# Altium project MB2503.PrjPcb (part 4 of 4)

## Sheet USB_TypeC_DRP.SchDoc: USB Type-C DRP
size A3; DocumentNumber: 13; Revision: A-01; SheetNumber: 13; SheetTotal: 17; Project: STM32MP15-BATTERY BOARD

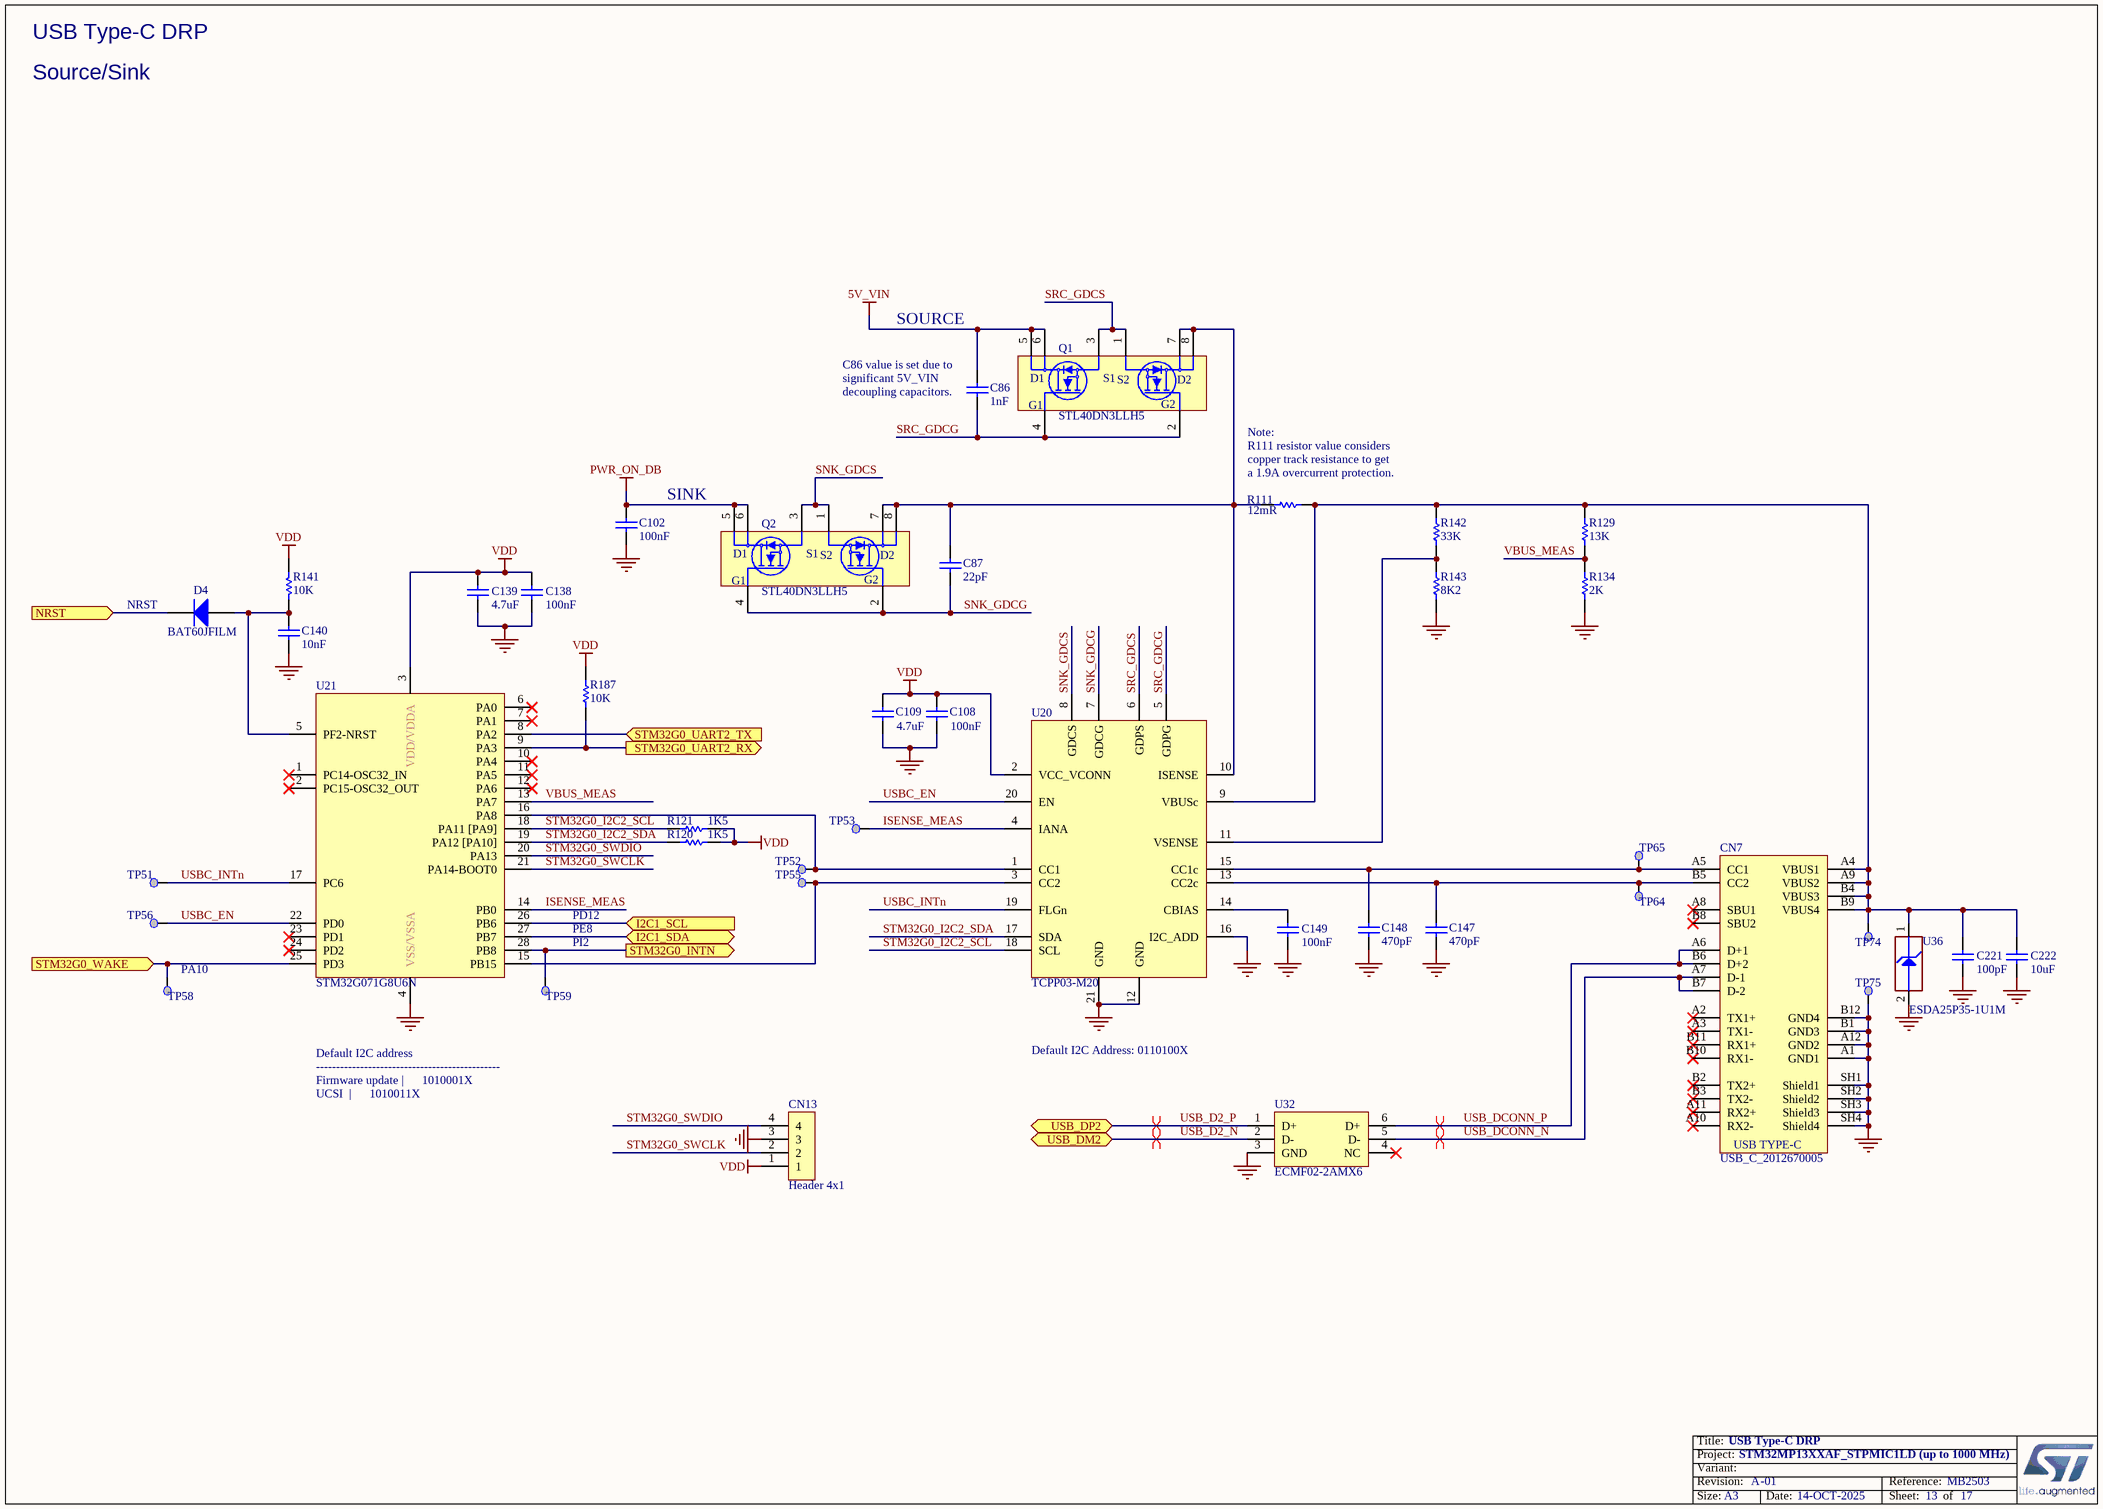
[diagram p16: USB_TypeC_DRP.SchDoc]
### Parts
C86  value 1nF  [C0402]  (hidden comment: Capacitor)
C87  value 22pF  [C0402]  (hidden comment: Capacitor)
C102  value 100nF  [C0402]  (hidden comment: Capacitor)
C108  value 100nF  [C0402]  (hidden comment: Capacitor)
C109  value 4.7uF  [C0402]  (hidden comment: Capacitor)
C138  value 100nF  [C0402]  (hidden comment: Capacitor)
C139  value 4.7uF  [C0402]  (hidden comment: Capacitor)
C140  value 10nF  [C0402]  (hidden comment: Capacitor)
C147  value 470pF  [C0402]  (hidden comment: Capacitor)
C148  value 470pF  [C0402]  (hidden comment: Capacitor)
C149  value 100nF  [C0603]  (hidden comment: Capacitor)
C221  value 100pF  [C0402]  (hidden comment: Capacitor)
C222  value 10uF  [C1210]  (hidden comment: Capacitor)
CN7  value USB_C_2012670005  [CON_USB-TYPEC_MOLEX_2012670005]  (hidden comment: USB_TYPE_C_Receptacle)
CN13  Header 4x1  [CON_SAMTEC_TSW-104-07-G-S]
D4  BAT60JFILM  [DIO_SOD323]
Q1  STL40DN3LLH5  [PowerFLAT_5x6]
Q2  STL40DN3LLH5  [PowerFLAT_5x6]
R111  value 12mR  [R0603_H070]  (hidden comment: Resistor)
R120  value 1K5  [R0402]  (hidden comment: Resistor)
R121  value 1K5  [R0402]  (hidden comment: Resistor)
R129  value 13K  [R0603]  (hidden comment: Resistor)
R134  value 2K  [R0603]  (hidden comment: Resistor)
R141  value 10K  [R0402]  (hidden comment: Resistor)
R142  value 33K  [R0603]  (hidden comment: Resistor)
R143  value 8K2  [R0603]  (hidden comment: Resistor)
R187  value 10K  [R0402]  (hidden comment: Resistor)
TP51  Test Point  [TP_SMD_1MM]  (value not drawn)  (no BOM)
TP52  Test Point  [TP_SMD_1MM]  (value not drawn)  (no BOM)
TP53  Test Point  [TP_SMD_1MM]  (value not drawn)  (no BOM)
TP55  Test Point  [TP_SMD_1MM]  (value not drawn)  (no BOM)
TP56  Test Point  [TP_SMD_1MM]  (value not drawn)  (no BOM)
TP58  Test Point  [TP_SMD_1MM]  (value not drawn)  (no BOM)
TP59  Test Point  [TP_SMD_1MM]  (value not drawn)  (no BOM)
TP64  Test Point  [TP_SMD_1MM]  (value not drawn)  (no BOM)
TP65  Test Point  [TP_SMD_1MM]  (value not drawn)  (no BOM)
TP74  Test Point  [TP_SMD_1MM]  (value not drawn)  (no BOM)
TP75  Test Point  [TP_SMD_1MM]  (value not drawn)  (no BOM)
U20  TCPP03-M20  [ICC_QFN20-EPAD_4X4_P050]
U21  STM32G071G8U6N  [ICC_UFQFPN28_4X4_P050]
U32  ECMF02-2AMX6  [ESD_QFN-6L_1P7X1P5_P050]
U36  value ESDA25P35-1U1M  [ESD_QFN1610_2N_1K_2A]  (hidden comment: ESD-TRANSIL)

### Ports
I2C1_SCL (in), I2C1_SDA (bidir), NRST (in), STM32G0_INTN (out), STM32G0_UART2_RX (out), STM32G0_UART2_TX (in), STM32G0_WAKE (in), USB_DM2 (bidir), USB_DP2 (bidir)

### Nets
5V_VIN: C86.2 Q1.5(D1) Q1.6(D1)
GND: C102.1 C108.1 C109.1 C138.1 C139.1 C140.1 C147.1 C148.1 C149.1 C221.1 C222.1 CN7.A1(GND1) CN7.A12(GND2) CN7.B1(GND3) CN7.B12(GND4) CN7.SH1(Shield1) CN7.SH2(Shield2) CN7.SH3(Shield3) CN7.SH4(Shield4) CN13.3 R134.1 R143.1 TP75.1 U20.12(GND) U20.16(I2C_ADD) U20.21(GND) U21.4(VSS/VSSA) U32.3(GND) U36.2(GND)
PWR_ON_DB: C102.2 Q2.5(D1) Q2.6(D1)
VDD: C108.2 C109.2 C138.2 C139.2 CN13.1 R120.2 R121.1 R141.2 R187.2 U20.2(VCC_VCONN) U21.3(VDD/VDDA)
I2C1_SCL: U21.26(PB6) ; port I2C1_SCL
I2C1_SDA: U21.27(PB7) ; port I2C1_SDA
ISENSE_MEAS: TP53.1 U20.4(IANA) U21.14(PB0)
NRST: D4.2(K) ; port NRST
SNK_GDCG: C87.1 Q2.2(G2) Q2.4(G1) U20.7(GDCG)
SNK_GDCS: Q2.1(S2) Q2.3(S1) U20.8(GDCS)
SRC_GDCG: C86.1 Q1.2(G2) Q1.4(G1) U20.5(GDPG)
SRC_GDCS: Q1.1(S2) Q1.3(S1) U20.6(GDPS)
STM32G0_I2C2_SCL: R121.2 U20.18(SCL) U21.18(PA11_[PA9])
STM32G0_I2C2_SDA: R120.1 U20.17(SDA) U21.19(PA12_[PA10])
STM32G0_INTN: TP59.1 U21.28(PB8) ; port STM32G0_INTN
STM32G0_SWCLK: CN13.2 U21.21(PA14-BOOT0)
STM32G0_SWDIO: CN13.4 U21.20(PA13)
STM32G0_UART2_RX: R187.1 U21.9(PA3) ; port STM32G0_UART2_RX
STM32G0_UART2_TX: U21.8(PA2) ; port STM32G0_UART2_TX
STM32G0_WAKE: TP58.1 U21.25(PD3) ; port STM32G0_WAKE
USB_D2_N: U32.2(D-) ; port USB_DM2
USB_D2_P: U32.1(D+) ; port USB_DP2
USB_DCONN_N: CN7.A7(D-1) CN7.B7(D-2) U32.5(D-)
USB_DCONN_P: CN7.A6(D+1) CN7.B6(D+2) U32.6(D+)
USBC_EN: TP56.1 U20.20(EN) U21.22(PD0)
USBC_INTn: TP51.1 U20.19(FLGn) U21.17(PC6)
VBUS_MEAS: R129.1 R134.2 U21.13(PA7)
NetC87_2: C87.2 Q1.7(D2) Q1.8(D2) Q2.7(D2) Q2.8(D2) R111.2 U20.10(ISENSE)
NetC140_2: C140.2 D4.1(A) R141.1 U21.5(PF2-NRST)
NetC147_2: C147.2 CN7.B5(CC2) TP64.1 U20.13(CC2c)
NetC148_2: C148.2 CN7.A5(CC1) TP65.1 U20.15(CC1c)
NetC149_2: C149.2 U20.14(CBIAS)
NetC221_2: C221.2 C222.2 CN7.A4(VBUS1) CN7.A9(VBUS2) CN7.B4(VBUS3) CN7.B9(VBUS4) R111.1 R129.2 R142.2 TP74.1 U20.9(VBUSc) U36.1(IO1)
NetR142_1: R142.1 R143.2 U20.11(VSENSE)
NetTP52_1: TP52.1 U20.1(CC1) U21.16(PA8)
NetTP55_1: TP55.1 U20.3(CC2) U21.15(PB15)

Not connected (* = marked no-connect by the designer): CN7 A2(TX1+)* A3(TX1-)* A8(SBU1)* A10(RX2-)* A11(RX2+)* B2(TX2+)* B3(TX2-)* B8(SBU2)* B10(RX1-)* B11(RX1+)*; U21 1(PC14-OSC32_IN)* 2(PC15-OSC32_OUT)* 6(PA0)* 7(PA1)* 10(PA4)* 11(PA5)* 12(PA6)* 23(PD1)* 24(PD2)*; U32 4(NC)*

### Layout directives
differential pair: USB_D2_N, USB_D2_P, USB_DCONN_N, USB_DCONN_P

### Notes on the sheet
- USB Type-C DRP
- Source/Sink
- SOURCE
- (near C86) C86 value is set due to significant 5V_VIN decoupling capacitors.
- SINK
- (near R111) Note:
  R111 resistor value considers copper track resistance to get a 1.9A overcurrent protection.
- (near D4) NRST
- PD12
- (near TP58) PA10
- PE8
- PI2
- Default I2C Address: 0110100X
- Default I2C address
  ----------------------------------------------
  Firmware update	|      1010001X
  UCSI		|      1010011X

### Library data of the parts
C86 = MCD-00198: Capacitor, MLCC, 1nF, 16V, X7R, +/-10%, 0402, T=0.5mm; Part_Preference: Recommended; Manufacturer: YAGEO; Manufacturer_Part_Number: CC0402KRX7R7BB102; Component_Country_Of_Origin: China; ShowFields: YES; ID: 2665
C87 = MCD-01995: Capacitor, MLCC, 22pF, 50V, C0G, +/-5%, 0402, T=0.5mm; Part_Preference: Recommended; Manufacturer: TDK; Manufacturer_Part_Number: C1005NP01H220J050BA; Partial_Alternate_Internal_Part_Number: MCD-04601; Component_Country_Of_Origin: Unknown; ShowFields: YES; ID: 4095
C102 C108 C138 = MCD-00006: Capacitor, MLCC, 100nF, 16V, X7R, +/-10%, 0402, T=0.5mm; Part_Preference: Recommended; Manufacturer: YAGEO; Manufacturer_Part_Number: CC0402KRX7R7BB104; Partial_Alternate_Internal_Part_Number: MCD-03299; Order_Code_RS: 9402047; Component_Country_Of_Origin: China; ShowFields: YES; ID: 2474
C109 C139 = MCD-01356: Capacitor, MLCC, 4.7uF, 6V3, X5R, +/-20%, 0402, T=0.5mm; Part_Preference: Recommended; Manufacturer: MURATA; Manufacturer_Part_Number: GRM155R60J475ME47; Partial_Alternate_Internal_Part_Number: MCD-04455; Order_Code_RS: 814-5230; Component_Country_Of_Origin: Japan°°; ShowFields: YES; ID: 3456
C140 = MCD-02198: Capacitor, MLCC, 10nF, 50V, X7R, +/-10%, 0402, T=0.5mm; Part_Preference: Recommended; Manufacturer: YAGEO; Manufacturer_Part_Number: CC0402KRX7R9BB103; Order_Code_RS: 6169644; Component_Country_Of_Origin: China; ShowFields: YES; ID: 4298
C147 C148 = MCD-00724: Capacitor, MLCC, 470pF, 50V, NPO, +/-5%, 0402, T=0.5mm; Manufacturer_Part_Number: CC0402JRNPO9BN471; Manufacturer: YAGEO; Part_Preference: Recommended; Order_Code_RS: 199-2186; Component_Country_Of_Origin: China; ShowFields: YES; ID: 3023
C149 = MCD-01099: Capacitor, MLCC, 100nF, 50V, X7R, +/-10%, 0603, T=0.8mm; BMS_Part_Number: 9142278; Part_Preference: Recommended; Manufacturer: YAGEO; Manufacturer_Part_Number: CC0603KRX7R9BB104; Order_Code_RS: 669-8767; Component_Country_Of_Origin: China; ShowFields: YES; ID: 3397
C221 = MCD-00205: Capacitor, MLCC, 100pF, 50V, NPO, +/-5%, 0402, T=0.5mm; Manufacturer_Part_Number: CC0402JRNPO9BN101; Manufacturer: YAGEO; Part_Preference: Recommended; Component_Country_Of_Origin: China; ShowFields: YES; ID: 2658
C222 = MCD-02378: Capacitor, MLCC, 10uF, 50V, X7R, +/-10%, 1210, T=2.5mm; Manufacturer_Part_Number: C3225X7R1H106K250AC; Manufacturer: TDK; Part_Preference: Recommended; Partial_Alternate_Internal_Part_Number: MCD-04210; Component_Country_Of_Origin: Japan°; ShowFields: YES; ID: 4484
CN7 = MCD-02421: USB_TypeC, 24 pins, RA, SMD, T=3.71mm (USB Certified 3.1); Part_Type: Connector; Manufacturer_Part_Number: 2012670005; Manufacturer: MOLEX; Part_Preference: Recommended; Order_Code_RS: 176-8434; Component_Country_Of_Origin: Unknown; ShowFields: YES; ID: 4527
CN13 = MCD-00029: Header, 4x1, 2.54mm, VR, TH, T=5.84mm/2.54mm; Part_Type: Connector; Manufacturer_Part_Number: TSW-104-07-G-S; Manufacturer: SAMTEC; Part_Preference: Recommended; Partial_Alternate_Internal_Part_Number: MCD-04227; Order_Code_RS: 161-2460; Component_Country_Of_Origin: China, Costa Rica, Malaysia, USA, Vietnam; ShowFields: YES; ID: 2487
D4 = MCD-00034: BMS_Part_Number: 9151097; Part_Preference: Recommended; Part_Type: Diode; Manufacturer: STMICROELECTRONICS; Manufacturer_HQ_COO: EU; Component_Country_Of_Origin: China; ShowFields: YES; ID: 2483; Order_Code_RS: 714-6879
Q1 Q2 = MCD-02152: MOSFET, Dual N-channel 30 V, 0.016 Ω typ., 40 A, STripFET™ H5 Power MOSFET; Part_Preference: Recommended; Part_Type: Transistor; Manufacturer: STMICROELECTRONICS; Manufacturer_HQ_COO: EU; Component_Country_Of_Origin: China; ShowFields: YES; ID: 4252
R111 = MCD-03129: Resistor, 12mR, 0603, +/-1%, 1/2W; Part_Preference: Recommended; Manufacturer: VISHAY; Manufacturer_Part_Number: WFCP0603R0120FE66; ShowFields: YES; ID: 5245; Component_Country_Of_Origin: Taiwan°
R120 R121 = MCD-00068: Resistor, 1K5, 0402, +/-1%, 1/16W; Part_Preference: Recommended; Manufacturer: YAGEO; Manufacturer_Part_Number: RC0402FR-071K5L; Order_Code_RS: 9239251; Component_Country_Of_Origin: China; ShowFields: YES; ID: 2524
R129 = MCD-00384: Resistor, 13K, 0603,+/-1%, 1/10W; Part_Preference: Recommended; Manufacturer: YAGEO; Manufacturer_Part_Number: RC0603FR-0713KL; Component_Country_Of_Origin: China; ShowFields: YES; ID: 2894
R134 = MCD-00420: Resistor, 2K ,0603, +/-1%, 1/10W; Part_Preference: Recommended; Manufacturer: YAGEO; Manufacturer_Part_Number: RC0603FR-072KL; Component_Country_Of_Origin: China; ShowFields: YES; ID: 2857
R141 = MCD-00053: Resistor, 10K, 0402, +/-1%, 1/16W; BMS_Part_Number: 9131590; Part_Preference: Recommended; Manufacturer: YAGEO; Manufacturer_Part_Number: RC0402FR-0710KL; Order_Code_RS: 9239359; Component_Country_Of_Origin: China; ShowFields: YES; ID: 2539
R142 = MCD-00259: Resistor, 33K, 0603, +/-1%, 1/10W; BMS_Part_Number: 9129771; Part_Preference: Recommended; Manufacturer: YAGEO; Manufacturer_Part_Number: RC0603FR-0733KL; Component_Country_Of_Origin: China; ShowFields: YES; ID: 2610
R143 = MCD-00530: Resistor, 8K2, 0603, +/-1%, 1/10W; Part_Preference: Recommended; Manufacturer: YAGEO; Manufacturer_Part_Number: RC0603FR-078K2L; Component_Country_Of_Origin: China; ShowFields: YES; ID: 3212
R187 = MCD-00053: Resistor, 10K, 0402, +/-1%, 1/16W; Manufacturer_Part_Number: RC0402FR-0710KL; Manufacturer: YAGEO; BMS_Part_Number: 9131590; Part_Preference: Recommended; Order_Code_RS: 9239359; Component_Country_Of_Origin: China; ShowFields: YES; ID: 2539
TP51-TP53 TP55 TP56 TP58 TP59 TP64 TP65 TP74 TP75 = MCD-00074: Test Point 1mm; Part_Type: Misc; Part_Preference: Recommended; ShowFields: YES; ID: 2518; Component_Country_Of_Origin: Unknown
U20 = MCD-02130: USB Type-C Port Protection for USB DRP Power Delivery, PPS compliant; Part_Preference: Recommended; Part_Type: IC; Manufacturer: STMICROELECTRONICS; Manufacturer_HQ_COO: EU; Component_Country_Of_Origin: China; ShowFields: YES; ID: 4230
U21 = MCD-02218: Arm Cortex-M0+ 32-bit MCU, up to 128 KB Flash, 36 KB RAM,  4x USART, timers, ADC, DAC, comm. I/Fs, 1.7-3.6V; Part_Preference: Recommended; Part_Type: IC; Manufacturer: STMICROELECTRONICS; Manufacturer_HQ_COO: EU; Component_Country_Of_Origin: China; ShowFields: YES; ID: 4318
U32 = MCD-00649: Common mode filter with ESD protection for USB 2.0 interface; Part_Type: Diode; Manufacturer: STMICROELECTRONICS; BMS_Part_Number: 9151138; Part_Preference: Recommended; Manufacturer_HQ_COO: EU; Component_Country_Of_Origin: China; ShowFields: YES; ID: 3094; Order_Code_RS: 880-5276
U36 = MCD-01207: High power Transient voltage suppressor:25V/35A EOS and ESD transients protection.; Part_Type: Diode; Manufacturer: STMICROELECTRONICS; Part_Preference: Recommended; Manufacturer_HQ_COO: EU; BMS_Part_Number: 9179045; Component_Country_Of_Origin: China; ShowFields: YES; ID: 3289; Order_Code_RS: 163-9774

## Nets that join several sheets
1V8_PERIPH: Power_Board (C99.2 U19.23), CSI_Camera_Bridge (21 pins)
3V3_AO: Ethernet1_RMII (9 pins), Power_Board (8 pins), WLAN_BLUETOOTH (C18.2 C19.2 U1.30), Expansion_Connector (C7.1 CN8.1 CN8.17), MCP_IO_expander (C22.2 C23.2 R9.1 U5.5)
3V3_SW: Ethernet2_RMII (9 pins), Power_Board (C115.2 U42.5 U42.6), LCD4.3 (C50.1 C53.2 CN16.4), USB_Host_Hub (18 pins), CSI_Camera_Bridge (C6.2 C117.2 CN1.15 R20.2)
5V_VIN: Power_Board (24 pins), ST-Link_V3E (D1.1), Expansion_Connector (C8.2 CN8.2 CN8.4), LCD4.3 (R35.1), USB_Host_Hub (C130.2 C135.2 L12.1), USB_TypeC_DRP (C86.2 Q1.5 Q1.6)
GND: Ethernet1_RMII (25 pins), Ethernet2_RMII (20 pins), Power_MPU (112 pins), Power_Board (62 pins), ST-Link_V3E (87 pins), WLAN_BLUETOOTH (23 pins), Expansion_Connector (10 pins), Peripherals (18 pins), MP135_11x11 (9 pins), LCD4.3 (23 pins), MCP_IO_expander (6 pins), USB_Host_Hub (53 pins), CSI_Camera_Bridge (47 pins), DDR3L_16bits (44 pins), USB_TypeC_DRP (29 pins)
VDD: Power_MPU (38 pins), Power_Board (C111.2 U19.3 U19.19 U22.2), ST-Link_V3E (R94.2), WLAN_BLUETOOTH (7 pins), Peripherals (8 pins), MP135_11x11 (8 pins), CSI_Camera_Bridge (R21.2), USB_TypeC_DRP (11 pins)
VDD_CORE: Power_MPU (23 pins), Power_Board (C110.2 C126.2 L9.2 U19.8)
VDD_CPU: Power_MPU (16 pins), Power_Board (5 pins)
VDD_DDR: Power_MPU (20 pins), Power_Board (R115.2 R116.2), DDR3L_16bits (34 pins)
VDD_SD: Power_Board (C144.2 U19.20), Peripherals (5 pins)
VDD_USB: Power_MPU (C119.2 U14.W14), Power_Board (C100.2 U19.18)
BOOT0: Peripherals (SW1.1), MP135_11x11 (U14.Y17)
BOOT1: Peripherals (SW1.2), MP135_11x11 (U14.AA15)
BOOT2: Peripherals (SW1.3), MP135_11x11 (U14.Y15)
BT_HOST_WAKE: WLAN_BLUETOOTH (U1.38), MP135_11x11 (R64.1)
BT_PCM_CLK: WLAN_BLUETOOTH (TP11.1 U1.11), MP135_11x11 (U14.E13)
BT_PCM_SDI: WLAN_BLUETOOTH (TP8.1 U1.10), MP135_11x11 (U14.B13)
BT_PCM_SDO: WLAN_BLUETOOTH (TP9.1 U1.9), MP135_11x11 (U14.E14)
BT_PCM_WS: WLAN_BLUETOOTH (TP1.1 U1.8), MP135_11x11 (U14.D14)
DCMI_D0: MP135_11x11 (U14.A2), CSI_Camera_Bridge (TP32.1 U4.13)
DCMI_D1: MP135_11x11 (U14.B1), CSI_Camera_Bridge (U4.14)
DCMI_D2: MP135_11x11 (U14.G2), CSI_Camera_Bridge (U4.16)
DCMI_D3: MP135_11x11 (U14.H2), CSI_Camera_Bridge (U4.17)
DCMI_D4: MP135_11x11 (U14.F3), CSI_Camera_Bridge (U4.19)
DCMI_D5: MP135_11x11 (U14.C2), CSI_Camera_Bridge (U4.20)
DCMI_D6: MP135_11x11 (U14.D1), CSI_Camera_Bridge (U4.22)
DCMI_D7: MP135_11x11 (U14.C3), CSI_Camera_Bridge (U4.23)
DCMI_HSYNC: MP135_11x11 (U14.E3), CSI_Camera_Bridge (TP21.1 U4.5)
DCMI_PIXCLK: MP135_11x11 (U14.C6), CSI_Camera_Bridge (TP13.1 U4.2)
DCMI_VSYNC: MP135_11x11 (U14.F2), CSI_Camera_Bridge (TP17.1 U4.3)
DFSDM1_CKOUT: Expansion_Connector (CN8.13), MP135_11x11 (U14.W6)
DFSDM1_DATIN3: Expansion_Connector (CN8.15), MP135_11x11 (U14.W4)
ETH1_CLK: Ethernet1_RMII (R107.1), MP135_11x11 (U14.Y1)
ETH1_CRS_DV: Ethernet1_RMII (R86.1), MP135_11x11 (U14.Y9)
ETH1_MDC: Ethernet1_RMII (U13.13), MP135_11x11 (U14.V3)
ETH1_MDINT: Ethernet1_RMII (R104.1), MP135_11x11 (U14.L4)
ETH1_MDIO: Ethernet1_RMII (R80.1 U13.12), MP135_11x11 (U14.Y4)
ETH1_RX_CLK: Ethernet1_RMII (R79.1), MP135_11x11 (U14.AA3)
ETH1_RXD0: Ethernet1_RMII (R98.1), MP135_11x11 (U14.Y7)
ETH1_RXD1: Ethernet1_RMII (R109.1), MP135_11x11 (U14.AA7)
ETH1_TX_EN: Ethernet1_RMII (U13.16), MP135_11x11 (U14.AA2)
ETH1_TXD0: Ethernet1_RMII (U13.17), MP135_11x11 (U14.AA9)
ETH1_TXD1: Ethernet1_RMII (U13.18), MP135_11x11 (U14.Y10)
ETH2_CLK: Ethernet2_RMII (R50.1), MP135_11x11 (U14.H5)
ETH2_CRS_DV: Ethernet2_RMII (R36.1), MP135_11x11 (U14.F4)
ETH2_MDC: Ethernet2_RMII (U7.13), MP135_11x11 (U14.G3)
ETH2_MDINT: Ethernet2_RMII (R30.1), MP135_11x11 (U14.H4)
ETH2_MDIO: Ethernet2_RMII (R31.1 U7.12), MP135_11x11 (U14.J3)
ETH2_RXD0: Ethernet2_RMII (R41.1), MP135_11x11 (U14.N2)
ETH2_RXD1: Ethernet2_RMII (R51.1), MP135_11x11 (U14.N1)
ETH2_TX_EN: Ethernet2_RMII (U7.16), MP135_11x11 (U14.G1)
ETH2_TXD0: Ethernet2_RMII (U7.17), MP135_11x11 (U14.P3)
ETH2_TXD1: Ethernet2_RMII (U7.18), MP135_11x11 (U14.R2)
EXP_GPIO2: Expansion_Connector (CN8.3), MP135_11x11 (R108.1 U14.N3), LCD4.3 (CN16.40), USB_Host_Hub (R166.1), CSI_Camera_Bridge (CN1.14 R170.2 TR1.3)
EXP_GPIO3: Expansion_Connector (CN8.5), MP135_11x11 (R82.1 U14.C5), LCD4.3 (CN16.39), USB_Host_Hub (R167.1), CSI_Camera_Bridge (CN1.13 R171.2 TR2.3)
EXP_GPIO4: Expansion_Connector (CN8.7), MP135_11x11 (U14.Y8)
EXP_GPIO5: Expansion_Connector (CN8.29), MP135_11x11 (TP50.1 U14.T2)
EXP_GPIO6: Expansion_Connector (CN8.31), MP135_11x11 (R96.2)
EXP_GPIO7: Expansion_Connector (CN8.26), MP135_11x11 (U14.H3)
EXP_GPIO8: Expansion_Connector (CN8.24), MP135_11x11 (U14.K3)
EXP_GPIO9: Expansion_Connector (CN8.21), MP135_11x11 (U14.P2)
EXP_GPIO10: Expansion_Connector (CN8.19), MP135_11x11 (U14.R3)
EXP_GPIO11: Expansion_Connector (CN8.23), MP135_11x11 (U14.J1)
EXP_GPIO12: Expansion_Connector (CN8.32), MP135_11x11 (U14.W10)
EXP_GPIO13: Expansion_Connector (CN8.33), MP135_11x11 (R85.1)
EXP_GPIO14: Expansion_Connector (CN8.8), MP135_11x11 (U14.W5)
EXP_GPIO15: Expansion_Connector (CN8.10), MP135_11x11 (U14.W8)
EXP_GPIO16: Expansion_Connector (CN8.36), MP135_11x11 (U14.V6)
EXP_GPIO17: Expansion_Connector (CN8.11), MP135_11x11 (U14.AA10)
EXP_GPIO18: Expansion_Connector (CN8.12), MP135_11x11 (U14.AA6)
EXP_GPIO19: Expansion_Connector (CN8.35), MP135_11x11 (U14.Y6)
EXP_GPIO20: Expansion_Connector (CN8.38), MP135_11x11 (U14.Y5)
EXP_GPIO21: Expansion_Connector (CN8.40), MP135_11x11 (U14.Y3)
EXP_GPIO23: Expansion_Connector (CN8.16), MP135_11x11 (U14.R1)
EXP_GPIO24: Expansion_Connector (CN8.18), MP135_11x11 (U14.W1)
EXP_GPIO25: Expansion_Connector (CN8.22), MP135_11x11 (U14.P5)
EXP_GPIO26: Expansion_Connector (CN8.37), MP135_11x11 (U14.E8)
I2C1_SCL: Expansion_Connector (CN8.28), MP135_11x11 (R62.1 U14.A6), MCP_IO_expander (R11.1), USB_TypeC_DRP (U21.26)
I2C1_SDA: Expansion_Connector (CN8.27), MP135_11x11 (R63.1 U14.B9), MCP_IO_expander (R10.1), USB_TypeC_DRP (U21.27)
I2C4_SCL: Power_Board (U19.13), MP135_11x11 (R75.1 U14.A9)
I2C4_SDA: Power_Board (U19.12), MP135_11x11 (R71.1 U14.A15)
LCD_B2: MP135_11x11 (U14.D6), LCD4.3 (CN16.23)
LCD_B3: MP135_11x11 (U14.D11), LCD4.3 (CN16.24)
LCD_B4: MP135_11x11 (U14.B8), LCD4.3 (CN16.25)
LCD_B5: MP135_11x11 (U14.B6), LCD4.3 (CN16.26)
LCD_B6: MP135_11x11 (U14.C1), LCD4.3 (CN16.27)
LCD_B7: MP135_11x11 (U14.B11), LCD4.3 (CN16.28)
LCD_BL: MP135_11x11 (U14.A4), LCD4.3 (R57.1)
LCD_CLK: MP135_11x11 (U14.C9), LCD4.3 (CN16.30 TP41.1)
LCD_DE: MP135_11x11 (U14.C12), LCD4.3 (CN16.34 TP40.1)
LCD_DISP: MP135_11x11 (U14.AA20), LCD4.3 (CN16.31 R59.2)
LCD_G2: MP135_11x11 (U14.A12), LCD4.3 (CN16.15)
LCD_G3: MP135_11x11 (U14.A13), LCD4.3 (CN16.16)
LCD_G4: MP135_11x11 (U14.C8), LCD4.3 (CN16.17)
LCD_G5: MP135_11x11 (U14.A7), LCD4.3 (CN16.18)
LCD_G6: MP135_11x11 (U14.C13), LCD4.3 (CN16.19)
LCD_G7: MP135_11x11 (U14.B4), LCD4.3 (CN16.20)
LCD_HSYNC: MP135_11x11 (U14.B14), LCD4.3 (CN16.32 TP43.1)
LCD_INT: MP135_11x11 (U14.B3), LCD4.3 (CN16.38 TP42.1)
LCD_R2: MP135_11x11 (U14.A10), LCD4.3 (CN16.7)
LCD_R3: MP135_11x11 (U14.C11), LCD4.3 (CN16.8)
LCD_R4: MP135_11x11 (U14.C4), LCD4.3 (CN16.9)
LCD_R5: MP135_11x11 (U14.D8), LCD4.3 (CN16.10)
LCD_R6: MP135_11x11 (U14.A3), LCD4.3 (CN16.11)
LCD_R7: MP135_11x11 (U14.B7), LCD4.3 (CN16.12)
LCD_RST: MP135_11x11 (U14.E2), LCD4.3 (CN16.37 R58.1)
LCD_VSYNC: MP135_11x11 (U14.B10), LCD4.3 (CN16.33 TP37.1)
LPO_32: WLAN_BLUETOOTH (R190.1 TP15.1), MP135_11x11 (U14.P4)
MCP_INT: MP135_11x11 (U14.W2), MCP_IO_expander (R12.1 R19.1 TP23.1)
NRST: Power_Board (U19.1), ST-Link_V3E (R88.2), Peripherals (6 pins), MP135_11x11 (C118.1 U14.Y11), MCP_IO_expander (U5.14), USB_TypeC_DRP (D4.2)
PA13: Peripherals (B2.1 B2.2 LD4.2), MP135_11x11 (U14.T4)
PA14: Peripherals (B1.1 B1.2 LD3.2), MP135_11x11 (U14.W13)
PF8_WKUP: Power_Board (U19.2), MP135_11x11 (U14.F1)
SDMMC1_CK: Peripherals (R33.2 R34.1 U6.6), MP135_11x11 (U14.A19)
SDMMC1_CMD: Peripherals (U6.5), MP135_11x11 (U14.C19)
SDMMC1_D0: Peripherals (U6.7), MP135_11x11 (U14.C18)
SDMMC1_D1: Peripherals (U6.8), MP135_11x11 (U14.A20)
SDMMC1_D2: Peripherals (U6.3), MP135_11x11 (U14.A18)
SDMMC1_D3: Peripherals (U6.4), MP135_11x11 (U14.B18)
SDMMC2_CK: WLAN_BLUETOOTH (TP27.1 U1.20), MP135_11x11 (U14.B17)
SDMMC2_CMD: WLAN_BLUETOOTH (R14.2 U1.22), MP135_11x11 (U14.C17)
SDMMC2_D0: WLAN_BLUETOOTH (R16.2 U1.24), MP135_11x11 (U14.B16)
SDMMC2_D1: WLAN_BLUETOOTH (R18.2 U1.26), MP135_11x11 (U14.B15)
SDMMC2_D2: WLAN_BLUETOOTH (R15.2 U1.23), MP135_11x11 (U14.C14)
SDMMC2_D3: WLAN_BLUETOOTH (R17.2 U1.25), MP135_11x11 (U14.C16)
STLINK_SWCLK: ST-Link_V3E (R90.2), MP135_11x11 (U14.Y2)
STLINK_SWDIO: ST-Link_V3E (R81.2), MP135_11x11 (U14.Y12)
STLINK_SWO: ST-Link_V3E (R61.2), MP135_11x11 (U14.W18)
STM32G0_INTN: MP135_11x11 (U14.N5), USB_TypeC_DRP (TP59.1 U21.28)
STM32G0_WAKE: MP135_11x11 (U14.AA19), USB_TypeC_DRP (TP58.1 U21.25)
T_JTDI: ST-Link_V3E (U12.L3), MP135_11x11 (R189.1)
TAMP_BTN: Peripherals (B4.1 B4.2 R181.1), MP135_11x11 (U14.U10)
USART2_CTS: WLAN_BLUETOOTH (TP6.1 U1.5), MP135_11x11 (U14.B2)
USART2_RTS: WLAN_BLUETOOTH (TP3.1 U1.4), MP135_11x11 (U14.C7)
USART2_RX: WLAN_BLUETOOTH (TP7.1 U1.3), MP135_11x11 (U14.E9)
USART2_TX: WLAN_BLUETOOTH (TP4.1 U1.2), MP135_11x11 (U14.D3)
USB_D1_N: MP135_11x11 (U14.AA16), USB_Host_Hub (U33.30)
USB_D1_P: MP135_11x11 (U14.Y16), USB_Host_Hub (U33.31)
USB_D2_N: MP135_11x11 (U14.Y13), USB_TypeC_DRP (U32.2)
USB_D2_P: MP135_11x11 (U14.AA13), USB_TypeC_DRP (U32.1)
USB_PWR_CC1: Power_Board (C156.2 R149.1), MP135_11x11 (U14.AA4)
USB_PWR_CC2: Power_Board (C151.1 R144.1), MP135_11x11 (U14.W9)
uSD_DETECT: Peripherals (CN3.9 R46.2 U10.1), MP135_11x11 (R188.1)
WL_HOST_WAKE: WLAN_BLUETOOTH (U1.27), MP135_11x11 (U14.A16)

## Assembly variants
MP135F: not fitted C1 C2 C3 C4 C21 C34 C54 C66 C72 C87 C102 C124 C133 CN9 CN13 Q2 R5 R19 R20 R24 R26 R34 R68 R73 R78 R107 R115 R141 R161 R164 R165 R166 R167 R170 R171 R189 R191 U40 U41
